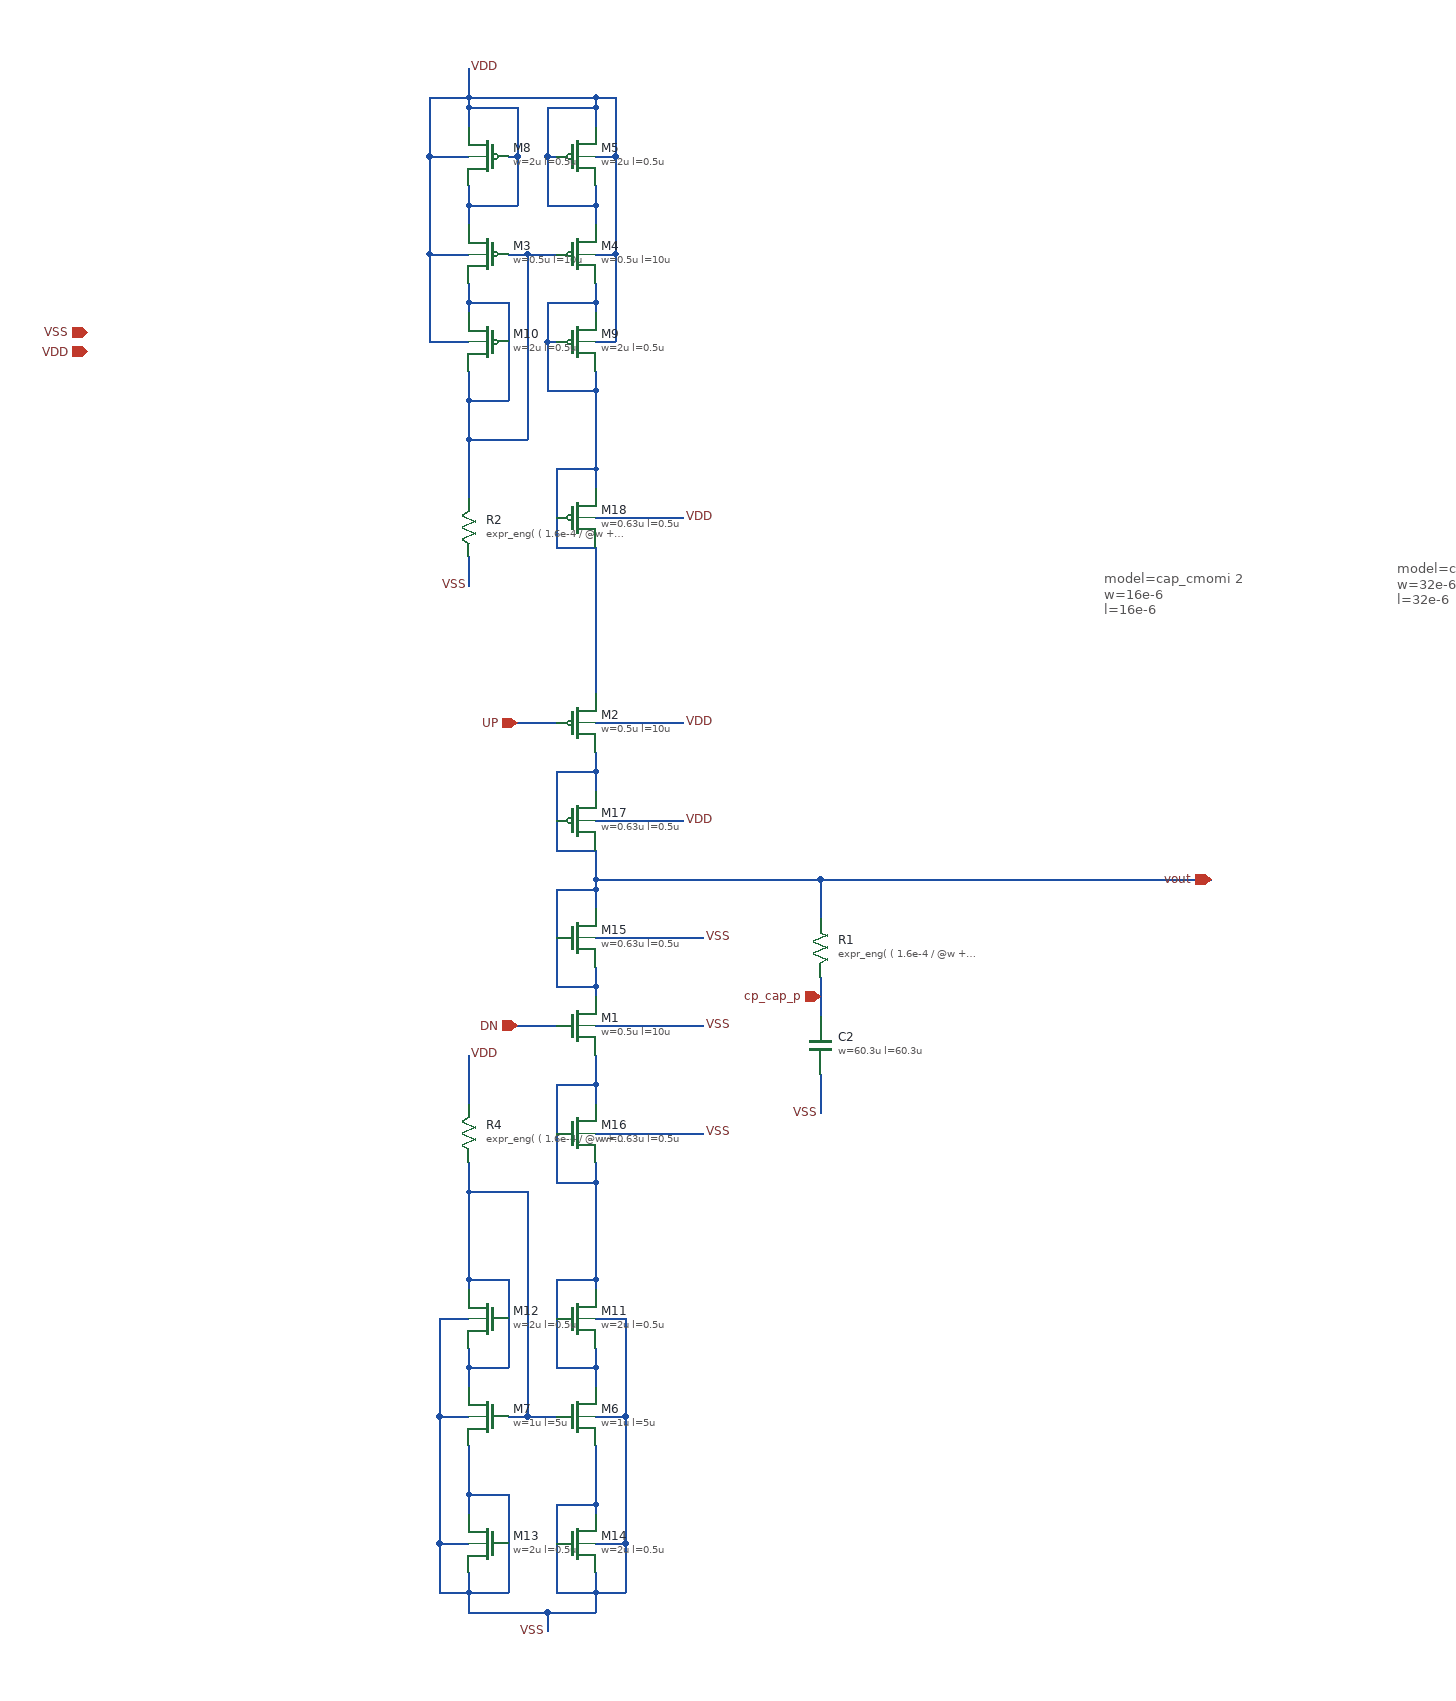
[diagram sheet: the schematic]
v {xschem version=3.4.8RC file_version=1.3}
G {}
K {}
V {}
S {}
F {}
E {}
T {model=cap_cmomi
w=32e-6
l=32e-6} 1710 -1210 0 0 0.4 0.4 {}
T {model=cap_cmomi 2
w=16e-6
l=16e-6} 1410 -1200 0 0 0.4 0.4 {}
N 890 -1040 980 -1040 {lab=VDD}
N 890 -730 1000 -730 {lab=VSS}
N 1120 -780 1120 -740 {lab=cp_cap_p}
N 1120 -680 1120 -640 {lab=VSS}
N 1120 -880 1120 -840 {lab=vout}
N 760 -560 820 -560 {lab=#net1}
N 820 -560 820 -330 {lab=#net1}
N 820 -330 850 -330 {lab=#net1}
N 840 -130 890 -130 {lab=VSS}
N 760 -560 760 -470 {lab=#net1}
N 760 -590 760 -560 {lab=#net1}
N 840 -130 840 -110 {lab=VSS}
N 760 -130 840 -130 {lab=VSS}
N 890 -240 890 -230 {lab=VSS}
N 890 -1680 910 -1680 {lab=VDD}
N 760 -1330 760 -1270 {lab=#net2}
N 760 -1330 820 -1330 {lab=#net2}
N 820 -1520 850 -1520 {lab=#net2}
N 760 -1710 760 -1680 {lab=VDD}
N 890 -1520 910 -1520 {lab=VDD}
N 760 -700 760 -650 {lab=VDD}
N 760 -1210 760 -1180 {lab=VSS}
N 1120 -880 1520 -880 {lab=vout}
N 890 -1570 890 -1550 {lab=VDD}
N 910 -1620 910 -1520 {lab=VDD}
N 890 -1620 910 -1620 {lab=VDD}
N 910 -1680 910 -1620 {lab=VDD}
N 840 -1570 890 -1570 {lab=VDD}
N 890 -1590 890 -1570 {lab=VDD}
N 840 -1620 840 -1570 {lab=VDD}
N 840 -1620 850 -1620 {lab=VDD}
N 840 -1670 840 -1620 {lab=VDD}
N 840 -1670 890 -1670 {lab=VDD}
N 890 -1670 890 -1650 {lab=VDD}
N 890 -1680 890 -1670 {lab=VDD}
N 760 -1680 890 -1680 {lab=VDD}
N 720 -1520 760 -1520 {lab=VDD}
N 760 -1570 760 -1550 {lab=VDD}
N 760 -1570 810 -1570 {lab=VDD}
N 760 -1590 760 -1570 {lab=VDD}
N 810 -1620 810 -1570 {lab=VDD}
N 800 -1620 810 -1620 {lab=VDD}
N 720 -1620 720 -1520 {lab=VDD}
N 720 -1620 760 -1620 {lab=VDD}
N 720 -1680 720 -1620 {lab=VDD}
N 720 -1680 760 -1680 {lab=VDD}
N 760 -1670 760 -1650 {lab=VDD}
N 810 -1670 810 -1620 {lab=VDD}
N 760 -1670 810 -1670 {lab=VDD}
N 760 -1680 760 -1670 {lab=VDD}
N 760 -1370 760 -1330 {lab=#net2}
N 840 -1380 890 -1380 {lab=#net3}
N 890 -1400 890 -1380 {lab=#net3}
N 840 -1430 840 -1380 {lab=#net3}
N 840 -1430 850 -1430 {lab=#net3}
N 760 -1370 800 -1370 {lab=#net2}
N 760 -1400 760 -1370 {lab=#net2}
N 800 -1470 800 -1370 {lab=#net2}
N 760 -1470 800 -1470 {lab=#net2}
N 760 -1470 760 -1460 {lab=#net2}
N 760 -1490 760 -1470 {lab=#net2}
N 720 -1520 720 -1430 {lab=VDD}
N 720 -1430 760 -1430 {lab=VDD}
N 820 -1520 820 -1330 {lab=#net2}
N 800 -1520 820 -1520 {lab=#net2}
N 840 -1470 840 -1430 {lab=#net3}
N 840 -1470 890 -1470 {lab=#net3}
N 890 -1490 890 -1470 {lab=#net3}
N 890 -1470 890 -1460 {lab=#net3}
N 890 -1430 910 -1430 {lab=VDD}
N 910 -1520 910 -1430 {lab=VDD}
N 760 -380 760 -360 {lab=#net1}
N 760 -380 800 -380 {lab=#net1}
N 760 -400 760 -380 {lab=#net1}
N 800 -470 800 -380 {lab=#net1}
N 760 -470 800 -470 {lab=#net1}
N 760 -470 760 -460 {lab=#net1}
N 890 -380 890 -360 {lab=#net4}
N 850 -380 890 -380 {lab=#net4}
N 890 -400 890 -380 {lab=#net4}
N 850 -470 850 -380 {lab=#net4}
N 850 -470 890 -470 {lab=#net4}
N 890 -470 890 -460 {lab=#net4}
N 800 -330 820 -330 {lab=#net1}
N 850 -240 850 -150 {lab=VSS}
N 850 -240 890 -240 {lab=VSS}
N 890 -170 890 -150 {lab=VSS}
N 850 -150 890 -150 {lab=VSS}
N 760 -250 760 -230 {lab=VSS}
N 800 -250 800 -150 {lab=VSS}
N 760 -250 800 -250 {lab=VSS}
N 760 -170 760 -150 {lab=VSS}
N 760 -150 800 -150 {lab=VSS}
N 760 -150 760 -130 {lab=VSS}
N 890 -150 890 -130 {lab=VSS}
N 890 -200 920 -200 {lab=VSS}
N 920 -200 920 -150 {lab=VSS}
N 890 -150 920 -150 {lab=VSS}
N 730 -200 760 -200 {lab=VSS}
N 730 -150 760 -150 {lab=VSS}
N 730 -200 730 -150 {lab=VSS}
N 890 -300 890 -240 {lab=VSS}
N 890 -330 920 -330 {lab=VSS}
N 730 -330 730 -200 {lab=VSS}
N 730 -330 760 -330 {lab=VSS}
N 760 -300 760 -250 {lab=VSS}
N 730 -430 730 -330 {lab=VSS}
N 730 -430 760 -430 {lab=VSS}
N 890 -770 890 -760 {lab=vout}
N 810 -730 850 -730 {lab=DN}
N 850 -770 890 -770 {lab=vout}
N 890 -790 890 -770 {lab=vout}
N 850 -870 850 -770 {lab=vout}
N 850 -870 890 -870 {lab=vout}
N 890 -870 890 -850 {lab=vout}
N 890 -820 1000 -820 {lab=VSS}
N 850 -570 890 -570 {lab=#net4}
N 890 -590 890 -570 {lab=#net4}
N 850 -670 850 -570 {lab=#net4}
N 850 -670 890 -670 {lab=#net4}
N 890 -670 890 -650 {lab=#net4}
N 890 -620 1000 -620 {lab=VSS}
N 890 -570 890 -470 {lab=#net4}
N 890 -700 890 -670 {lab=#net4}
N 890 -990 890 -970 {lab=vout}
N 890 -880 890 -870 {lab=vout}
N 850 -910 890 -910 {lab=vout}
N 850 -990 850 -910 {lab=vout}
N 850 -990 890 -990 {lab=vout}
N 890 -1010 890 -990 {lab=vout}
N 890 -940 980 -940 {lab=VDD}
N 850 -1220 890 -1220 {lab=#net3}
N 850 -1300 850 -1220 {lab=#net3}
N 850 -1300 890 -1300 {lab=#net3}
N 890 -1250 980 -1250 {lab=VDD}
N 890 -1300 890 -1280 {lab=#net3}
N 890 -880 1120 -880 {lab=vout}
N 890 -910 890 -880 {lab=vout}
N 890 -430 920 -430 {lab=VSS}
N 920 -330 920 -200 {lab=VSS}
N 920 -430 920 -330 {lab=VSS}
N 890 -1380 890 -1300 {lab=#net3}
N 890 -1220 890 -1070 {lab=#net3}
N 810 -1040 850 -1040 {lab=UP}
C {title-3.sym} 0 0 0 0 {name=l1 author="Belal Elshinnawey" rev=1.0 lock=true}
C {devices/iopin.sym} 370 -1420 2 0 {name=p6 lab=VDD}
C {devices/iopin.sym} 370 -1440 2 0 {name=p7 lab=VSS}
C {devices/lab_pin.sym} 980 -1040 2 0 {name=lp13 sig_type=std_logic lab=VDD}
C {devices/lab_pin.sym} 760 -700 0 1 {name=l10 sig_type=std_logic lab=VDD}
C {devices/lab_pin.sym} 760 -1710 0 1 {name=l12 sig_type=std_logic lab=VDD}
C {rhigh_ps.sym} 760 -1240 0 1 {name=R2
w=0.50e-6
l=80.585e-6
ps=0.18e-6
model=rhigh
body=VSS
spiceprefix=X
b=25
 m=1
  mm_ok=1
value="expr_eng(  ( 1.6e-4 / @w + 1360.0 * ( (@b + 1)* @l + ( 1.081*( @w - 0.04e-6 ) + 0.18e-6 )*@b ) / ( @w - 0.04e-6 ) ) / @m  )"
}
C {sg13cmos5l_pr/sg13_lv_pmos.sym} 780 -1520 0 1 {name=M3
l=10u
w=0.5u
ng=1
m=1
mm_ok=1
model=sg13_lv_pmos
spiceprefix=X
}
C {sg13cmos5l_pr/sg13_lv_pmos.sym} 870 -1520 0 0 {name=M4
l=10u
w=0.5u
ng=1
m=1
mm_ok=1
model=sg13_lv_pmos
spiceprefix=X

}
C {sg13cmos5l_pr/sg13_lv_pmos.sym} 870 -1040 0 0 {name=M2
l=10u
w=0.5u
ng=1
m=1
mm_ok=1
model=sg13_lv_pmos
spiceprefix=X

}
C {sg13cmos5l_pr/sg13_lv_nmos.sym} 870 -330 0 0 {name=M6
l=5u
w=1u
ng=1
 m=1
  mm_ok=1
 model=sg13_lv_nmos
spiceprefix=X
}
C {sg13cmos5l_pr/sg13_lv_nmos.sym} 780 -330 0 1 {name=M7
l=5u
w=1u
ng=1
 m=1
  mm_ok=1
 model=sg13_lv_nmos
spiceprefix=X
}
C {sg13cmos5l_pr/sg13_lv_nmos.sym} 870 -730 0 0 {name=M1
l=10u
w=0.5u
ng=1
 m=1
  mm_ok=1
 model=sg13_lv_nmos
spiceprefix=X
}
C {rhigh_ps.sym} 1120 -810 0 0 {name=R1
w=0.50e-6
l=40.11e-6
model=rhigh
ps=0.18e-6
body=VSS
spiceprefix=X
b=20
 m=1
  mm_ok=1
value="expr_eng(  ( 1.6e-4 / @w + 1360.0 * ( (@b + 1)* @l + ( 1.081*( @w - 0.04e-6 ) + 0.18e-6 )*@b ) / ( @w - 0.04e-6 ) ) / @m  )"
}
C {devices/ipin.sym} 810 -1040 0 0 {name=p2 lab=UP}
C {devices/ipin.sym} 810 -730 0 0 {name=p3 lab=DN}
C {devices/iopin.sym} 1520 -880 0 0 {name=p5 lab=vout}
C {devices/lab_pin.sym} 760 -1180 0 0 {name=lp1 sig_type=std_logic lab=VSS}
C {devices/lab_pin.sym} 840 -110 0 0 {name=lp2 sig_type=std_logic lab=VSS}
C {devices/lab_pin.sym} 1000 -730 2 0 {name=lp3 sig_type=std_logic lab=VSS}
C {devices/lab_pin.sym} 1120 -640 0 0 {name=lp4 sig_type=std_logic lab=VSS}
C {rhigh_ps.sym} 760 -620 0 1 {name=R4
w=0.50e-6
l=40.585e-6
ps=0.18e-6
model=rhigh
body=VSS
spiceprefix=X
b=25
 m=1
  mm_ok=1
value="expr_eng(  ( 1.6e-4 / @w + 1360.0 * ( (@b + 1)* @l + ( 1.081*( @w - 0.04e-6 ) + 0.18e-6 )*@b ) / ( @w - 0.04e-6 ) ) / @m  )"
}
C {sg13cmos5l_pr/sg13_lv_pmos.sym} 870 -1620 0 0 {name=M5
l=0.5u
w=2u
ng=1
m=1
mm_ok=1
model=sg13_lv_pmos
spiceprefix=X

}
C {sg13cmos5l_pr/sg13_lv_pmos.sym} 780 -1620 0 1 {name=M8
l=0.5u
w=2u
ng=1
m=1
mm_ok=1
model=sg13_lv_pmos
spiceprefix=X

}
C {sg13cmos5l_pr/sg13_lv_pmos.sym} 870 -1430 0 0 {name=M9
l=0.5u
w=2u
ng=1
m=1
mm_ok=1
model=sg13_lv_pmos
spiceprefix=X

}
C {sg13cmos5l_pr/sg13_lv_pmos.sym} 780 -1430 0 1 {name=M10
l=0.5u
w=2u
ng=1
m=1
mm_ok=1
model=sg13_lv_pmos
spiceprefix=X

}
C {sg13cmos5l_pr/sg13_lv_nmos.sym} 870 -430 0 0 {name=M11
l=0.5u
w=2u
ng=1
 m=1
  mm_ok=1
 model=sg13_lv_nmos
spiceprefix=X
}
C {sg13cmos5l_pr/sg13_lv_nmos.sym} 780 -430 0 1 {name=M12
l=0.5u
w=2u
ng=1
 m=1
  mm_ok=1
 model=sg13_lv_nmos
spiceprefix=X
}
C {sg13cmos5l_pr/sg13_lv_nmos.sym} 780 -200 0 1 {name=M13
l=0.5u
w=2u
ng=1
 m=1
  mm_ok=1
 model=sg13_lv_nmos
spiceprefix=X
}
C {sg13cmos5l_pr/sg13_lv_nmos.sym} 870 -200 0 0 {name=M14
l=0.5u
w=2u
ng=1
 m=1
  mm_ok=1
 model=sg13_lv_nmos
spiceprefix=X
}
C {sg13cmos5l_pr/sg13_lv_nmos.sym} 870 -820 0 0 {name=M15
l=0.5u
w=0.63u
ng=1
 m=1
  mm_ok=1
 model=sg13_lv_nmos
spiceprefix=X
}
C {devices/lab_pin.sym} 1000 -820 2 0 {name=lp5 sig_type=std_logic lab=VSS}
C {sg13cmos5l_pr/sg13_lv_nmos.sym} 870 -620 0 0 {name=M16
l=0.5u
w=0.63u
ng=1
 m=1
  mm_ok=1
 model=sg13_lv_nmos
spiceprefix=X
}
C {devices/lab_pin.sym} 1000 -620 2 0 {name=lp7 sig_type=std_logic lab=VSS}
C {sg13cmos5l_pr/sg13_lv_pmos.sym} 870 -940 0 0 {name=M17
l=0.5u
w=0.63u
ng=1
m=1
mm_ok=1
model=sg13_lv_pmos
spiceprefix=X

}
C {devices/lab_pin.sym} 980 -940 2 0 {name=lp8 sig_type=std_logic lab=VDD}
C {sg13cmos5l_pr/sg13_lv_pmos.sym} 870 -1250 0 0 {name=M18
l=0.5u
w=0.63u
ng=1
m=1
mm_ok=1
model=sg13_lv_pmos
spiceprefix=X

}
C {devices/lab_pin.sym} 980 -1250 2 0 {name=lp9 sig_type=std_logic lab=VDD}
C {sg13cmos5l_pr/cap_mfringe.sym} 1120 -710 0 0 {name=C2
model=cap_mfringe
w=60.3u
l=60.3u
mmin=1
mmax=4
spiceprefix=X
spice_ignore=false}
C {devices/iopin.sym} 1120 -760 2 0 {name=p4 lab=cp_cap_p}
